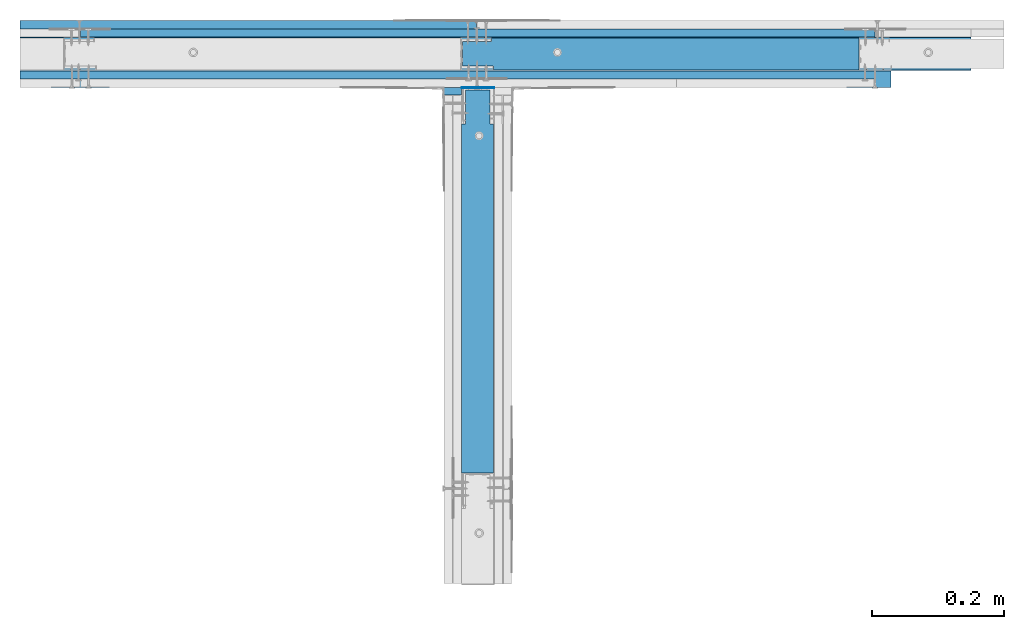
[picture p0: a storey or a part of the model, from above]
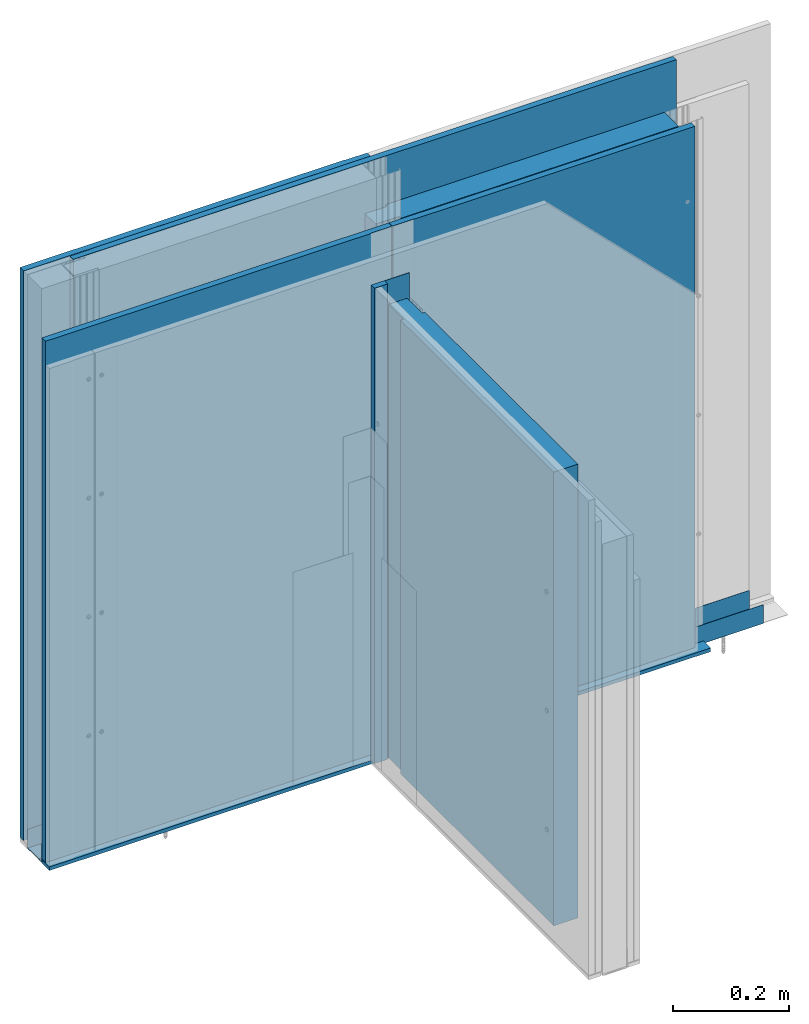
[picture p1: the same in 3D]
Properties of the parts of a building model (IFC2X3)

# File
Description: ViewDefinition [CoordinationView]
Time: 2022-01-07T10:55:04
Made in: SketchUp Pro 2015

# IfcProject, Default Project
Description: Description of Default Project

# IfcSite, Default Site
Description: Description of Default Site; RefLatitude: 24, 28, 0; RefLongitude: 54, 25, 0; RefElevation: 10 mm

# IfcBuilding, Default Building
Description: Description of Default Building

# IfcBuildingStorey, Default Building Storey
In: Default Building
Description: Description of Default Building Storey; Elevation: 0 mm

# IfcWall (142)
In: Default Building Storey
Description: Description of Object
Name
14 x Dedykowana masa szpachlowa Rigips - konstrukcyjna
5 x Profil RIGIPS CW50 ULTRASTIL®
2 x Profil RIGIPS UW 50 ULTRASTIL®
3 x Taśma uszczelniająca piankowa RIGIPS
5 x Wełna mineralna szklana lub skalna ISOVER
10 x Kołek rozporowy min. fi 6
15 x Płyta gipsowo-kartonowa RIGIPS PRO (4PRO™)
2 x Taśma narożnikowa HABITO® NO-COAT® | dynamic_attributes - _has_movetool_behaviors: 0; _lengthunits: CENTIMETERS; _name: Taśma narożnikowa HABITO® NOCOAT®; _formatversion: 1; _lastmodified: 2021-12-02 11:34; IfcPropertySet - _last_lenx: 01.77165; _last_leny: 01.771651.77165; _last_lenz: 01.771651.7716523.5571
6 x Dedykowana masa szpachlowa Rigips - wykończeniowa
28 x Wkręt RIGIPS TN 25
46 x Wkręt RIGIPS TN 35
2 x Taśma spoinowa RIGIPS
4 x Wkręt RIGIPS TN 45
